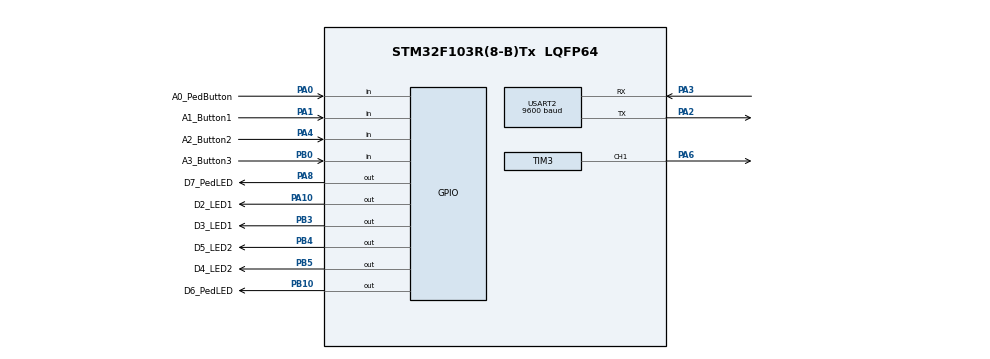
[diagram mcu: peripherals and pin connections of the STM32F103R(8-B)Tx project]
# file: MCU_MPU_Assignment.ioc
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Mcu.Family=STM32F1
Mcu.Name=STM32F103R(8-B)Tx
Mcu.Package=LQFP64
NVIC.PriorityGroup=NVIC_PRIORITYGROUP_4
NVIC.TIM2_IRQn=true\:0\:0\:false\:false\:true\:true\:true
NVIC.TIM3_IRQn=true\:0\:0\:false\:false\:true\:true\:true
NVIC.USART2_IRQn=true\:0\:0\:false\:false\:true\:true\:true
PA0-WKUP.GPIO_Label=A0_PedButton
PA0-WKUP.GPIO_PuPd=GPIO_PULLUP
PA0-WKUP.Signal=GPIO_Input
PA1.GPIO_Label=A1_Button1
PA1.GPIO_PuPd=GPIO_PULLUP
PA1.Signal=GPIO_Input
PA10.GPIO_Label=D2_LED1
PA10.Signal=GPIO_Output
PA13.Mode=Serial_Wire
PA13.Signal=SYS_JTMS-SWDIO
PA14.Mode=Serial_Wire
PA14.Signal=SYS_JTCK-SWCLK
PA2.Mode=Asynchronous
PA2.Signal=USART2_TX
PA3.Mode=Asynchronous
PA3.Signal=USART2_RX
PA4.GPIO_Label=A2_Button2
PA4.GPIO_PuPd=GPIO_PULLUP
PA4.Signal=GPIO_Input
PA6.Signal=S_TIM3_CH1
PA8.GPIO_Label=D7_PedLED
PA8.Signal=GPIO_Output
PB0.GPIO_Label=A3_Button3
PB0.GPIO_PuPd=GPIO_PULLUP
PB0.Signal=GPIO_Input
PB10.GPIO_Label=D6_PedLED
PB10.Signal=GPIO_Output
PB3.GPIO_Label=D3_LED1
PB3.Signal=GPIO_Output
PB4.GPIO_Label=D5_LED2
PB4.Signal=GPIO_Output
PB5.GPIO_Label=D4_LED2
PB5.Signal=GPIO_Output
ProjectManager.HeapSize=0x200
ProjectManager.StackSize=0x400
ProjectManager.TargetToolchain=STM32CubeIDE
RCC.APB1Freq_Value=8000000
RCC.APB2Freq_Value=8000000
SH.S_TIM3_CH1.0=TIM3_CH1,PWM Generation1 CH1
TIM2.Period=9
TIM2.Prescaler=7999
TIM3.Channel-PWM\ Generation1\ CH1=TIM_CHANNEL_1
TIM3.Period=9
TIM3.Prescaler=7999
USART2.BaudRate=9600
USART2.VirtualMode=VM_ASYNC
VP_TIM2_VS_ClockSourceINT.Mode=Internal
VP_TIM3_VS_ClockSourceINT.Mode=Internal
board=custom

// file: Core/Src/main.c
/* USER CODE BEGIN Header */
/**
  ******************************************************************************
  * @file           : main.c
  * @brief          : Main program body
  ******************************************************************************
  * @attention
  *
  * <h2><center>&copy; Copyright (c) 2023 STMicroelectronics.
  * All rights reserved.</center></h2>
  *
  * This software component is licensed by ST under BSD 3-Clause license,
  * the "License"; You may not use this file except in compliance with the
  * License. You may obtain a copy of the License at:
  *                        opensource.org/licenses/BSD-3-Clause
  *
  ******************************************************************************
  */
/* USER CODE END Header */
#include "main.h"

/* USER CODE BEGIN Includes */
#include "global.h"
#include "timer.h"
#include "fsm_automatic.h"
#include "fsm_manual.h"
#include "input_processing.h"
#include "input_reading.h"
#include "uart.h"
#include "scheduler.h"
/* USER CODE END Includes */

TIM_HandleTypeDef htim2;
TIM_HandleTypeDef htim3;

UART_HandleTypeDef huart2;

void SystemClock_Config(void);
static void MX_GPIO_Init(void);
static void MX_TIM2_Init(void);
static void MX_TIM3_Init(void);
static void MX_USART2_UART_Init(void);

/* USER CODE BEGIN 0 */
void buzzer(int vol){
	__HAL_TIM_SET_COMPARE(&htim3, TIM_CHANNEL_1, vol);
}
/* USER CODE END 0 */

int main(void)
{

  /* MCU Configuration--------------------------------------------------------*/

  /* Reset of all peripherals, Initializes the Flash interface and the Systick. */
  HAL_Init();

  /* Configure the system clock */
  SystemClock_Config();

  /* Initialize all configured peripherals */
  MX_GPIO_Init();
  MX_TIM2_Init();
  MX_TIM3_Init();
  MX_USART2_UART_Init();
  /* USER CODE BEGIN 2 */
  HAL_TIM_Base_Start_IT(&htim2);
  HAL_TIM_Base_Start_IT(&htim3);
  HAL_TIM_PWM_Start(&htim3, TIM_CHANNEL_1);

  setTimer6(500);
  SCH_Add_Task(timer_run, 0, 1);
  SCH_Add_Task(button_reading, 0, 1);
  SCH_Add_Task(fsm_automatic, 0, 1);
  SCH_Add_Task(fsm_red_manual, 0, 1);
  SCH_Add_Task(fsm_amber_manual, 0, 1);
  SCH_Add_Task(fsm_green_manual, 0, 1);
  SCH_Add_Task(fsm_button_processing, 0, 1);
  /* USER CODE END 2 */

  /* Infinite loop */
  /* USER CODE BEGIN WHILE */
  while (1)
  {
	  SCH_Dispatch_Tasks();
    /* USER CODE END WHILE */

  }
}

void SystemClock_Config(void)
{
  RCC_OscInitTypeDef RCC_OscInitStruct = {0};
  RCC_ClkInitTypeDef RCC_ClkInitStruct = {0};

  /** Initializes the RCC Oscillators according to the specified parameters
  * in the RCC_OscInitTypeDef structure.
  */
  RCC_OscInitStruct.OscillatorType = RCC_OSCILLATORTYPE_HSI;
  RCC_OscInitStruct.HSIState = RCC_HSI_ON;
  RCC_OscInitStruct.HSICalibrationValue = RCC_HSICALIBRATION_DEFAULT;
  RCC_OscInitStruct.PLL.PLLState = RCC_PLL_ON;
  RCC_OscInitStruct.PLL.PLLSource = RCC_PLLSOURCE_HSI_DIV2;
  RCC_OscInitStruct.PLL.PLLMUL = RCC_PLL_MUL2;
  if (HAL_RCC_OscConfig(&RCC_OscInitStruct) != HAL_OK)
  {
    Error_Handler();
  }

  /** Initializes the CPU, AHB and APB buses clocks
  */
  RCC_ClkInitStruct.ClockType = RCC_CLOCKTYPE_HCLK|RCC_CLOCKTYPE_SYSCLK
                              |RCC_CLOCKTYPE_PCLK1|RCC_CLOCKTYPE_PCLK2;
  RCC_ClkInitStruct.SYSCLKSource = RCC_SYSCLKSOURCE_PLLCLK;
  RCC_ClkInitStruct.AHBCLKDivider = RCC_SYSCLK_DIV1;
  RCC_ClkInitStruct.APB1CLKDivider = RCC_HCLK_DIV2;
  RCC_ClkInitStruct.APB2CLKDivider = RCC_HCLK_DIV1;

  if (HAL_RCC_ClockConfig(&RCC_ClkInitStruct, FLASH_LATENCY_0) != HAL_OK)
  {
    Error_Handler();
  }
}

static void MX_TIM2_Init(void)
{

  TIM_ClockConfigTypeDef sClockSourceConfig = {0};
  TIM_MasterConfigTypeDef sMasterConfig = {0};

  htim2.Instance = TIM2;
  htim2.Init.Prescaler = 7999;
  htim2.Init.CounterMode = TIM_COUNTERMODE_UP;
  htim2.Init.Period = 9;
  htim2.Init.ClockDivision = TIM_CLOCKDIVISION_DIV1;
  htim2.Init.AutoReloadPreload = TIM_AUTORELOAD_PRELOAD_DISABLE;
  if (HAL_TIM_Base_Init(&htim2) != HAL_OK)
  {
    Error_Handler();
  }
  sClockSourceConfig.ClockSource = TIM_CLOCKSOURCE_INTERNAL;
  if (HAL_TIM_ConfigClockSource(&htim2, &sClockSourceConfig) != HAL_OK)
  {
    Error_Handler();
  }
  sMasterConfig.MasterOutputTrigger = TIM_TRGO_RESET;
  sMasterConfig.MasterSlaveMode = TIM_MASTERSLAVEMODE_DISABLE;
  if (HAL_TIMEx_MasterConfigSynchronization(&htim2, &sMasterConfig) != HAL_OK)
  {
    Error_Handler();
  }

}

static void MX_TIM3_Init(void)
{

  TIM_ClockConfigTypeDef sClockSourceConfig = {0};
  TIM_MasterConfigTypeDef sMasterConfig = {0};
  TIM_OC_InitTypeDef sConfigOC = {0};

  htim3.Instance = TIM3;
  htim3.Init.Prescaler = 7999;
  htim3.Init.CounterMode = TIM_COUNTERMODE_UP;
  htim3.Init.Period = 9;
  htim3.Init.ClockDivision = TIM_CLOCKDIVISION_DIV1;
  htim3.Init.AutoReloadPreload = TIM_AUTORELOAD_PRELOAD_DISABLE;
  if (HAL_TIM_Base_Init(&htim3) != HAL_OK)
  {
    Error_Handler();
  }
  sClockSourceConfig.ClockSource = TIM_CLOCKSOURCE_INTERNAL;
  if (HAL_TIM_ConfigClockSource(&htim3, &sClockSourceConfig) != HAL_OK)
  {
    Error_Handler();
  }
  if (HAL_TIM_PWM_Init(&htim3) != HAL_OK)
  {
    Error_Handler();
  }
  sMasterConfig.MasterOutputTrigger = TIM_TRGO_RESET;
  sMasterConfig.MasterSlaveMode = TIM_MASTERSLAVEMODE_DISABLE;
  if (HAL_TIMEx_MasterConfigSynchronization(&htim3, &sMasterConfig) != HAL_OK)
  {
    Error_Handler();
  }
  sConfigOC.OCMode = TIM_OCMODE_PWM1;
  sConfigOC.Pulse = 0;
  sConfigOC.OCPolarity = TIM_OCPOLARITY_HIGH;
  sConfigOC.OCFastMode = TIM_OCFAST_DISABLE;
  if (HAL_TIM_PWM_ConfigChannel(&htim3, &sConfigOC, TIM_CHANNEL_1) != HAL_OK)
  {
    Error_Handler();
  }
  HAL_TIM_MspPostInit(&htim3);

}

static void MX_USART2_UART_Init(void)
{

  huart2.Instance = USART2;
  huart2.Init.BaudRate = 9600;
  huart2.Init.WordLength = UART_WORDLENGTH_8B;
  huart2.Init.StopBits = UART_STOPBITS_1;
  huart2.Init.Parity = UART_PARITY_NONE;
  huart2.Init.Mode = UART_MODE_TX_RX;
  huart2.Init.HwFlowCtl = UART_HWCONTROL_NONE;
  huart2.Init.OverSampling = UART_OVERSAMPLING_16;
  if (HAL_UART_Init(&huart2) != HAL_OK)
  {
    Error_Handler();
  }

}

static void MX_GPIO_Init(void)
{
  GPIO_InitTypeDef GPIO_InitStruct = {0};

  /* GPIO Ports Clock Enable */
  __HAL_RCC_GPIOA_CLK_ENABLE();
  __HAL_RCC_GPIOB_CLK_ENABLE();

  /*Configure GPIO pin Output Level */
  HAL_GPIO_WritePin(GPIOB, D6_PedLED_Pin|D3_LED1_Pin|D5_LED2_Pin|D4_LED2_Pin, GPIO_PIN_RESET);

  /*Configure GPIO pin Output Level */
  HAL_GPIO_WritePin(GPIOA, D7_PedLED_Pin|D2_LED1_Pin, GPIO_PIN_RESET);

  /*Configure GPIO pins : A0_PedButton_Pin A1_Button1_Pin A2_Button2_Pin */
  GPIO_InitStruct.Pin = A0_PedButton_Pin|A1_Button1_Pin|A2_Button2_Pin;
  GPIO_InitStruct.Mode = GPIO_MODE_INPUT;
  GPIO_InitStruct.Pull = GPIO_NOPULL;
  HAL_GPIO_Init(GPIOA, &GPIO_InitStruct);

  /*Configure GPIO pin : A3_Button3_Pin */
  GPIO_InitStruct.Pin = A3_Button3_Pin;
  GPIO_InitStruct.Mode = GPIO_MODE_INPUT;
  GPIO_InitStruct.Pull = GPIO_NOPULL;
  HAL_GPIO_Init(A3_Button3_GPIO_Port, &GPIO_InitStruct);

  /*Configure GPIO pins : D6_PedLED_Pin D3_LED1_Pin D5_LED2_Pin D4_LED2_Pin */
  GPIO_InitStruct.Pin = D6_PedLED_Pin|D3_LED1_Pin|D5_LED2_Pin|D4_LED2_Pin;
  GPIO_InitStruct.Mode = GPIO_MODE_OUTPUT_PP;
  GPIO_InitStruct.Pull = GPIO_NOPULL;
  GPIO_InitStruct.Speed = GPIO_SPEED_FREQ_LOW;
  HAL_GPIO_Init(GPIOB, &GPIO_InitStruct);

  /*Configure GPIO pins : D7_PedLED_Pin D2_LED1_Pin */
  GPIO_InitStruct.Pin = D7_PedLED_Pin|D2_LED1_Pin;
  GPIO_InitStruct.Mode = GPIO_MODE_OUTPUT_PP;
  GPIO_InitStruct.Pull = GPIO_NOPULL;
  GPIO_InitStruct.Speed = GPIO_SPEED_FREQ_LOW;
  HAL_GPIO_Init(GPIOA, &GPIO_InitStruct);

}

/* USER CODE BEGIN 4 */
void HAL_TIM_PeriodElapsedCallback(TIM_HandleTypeDef *htim2) {
	SCH_Update();
}
/* USER CODE END 4 */

void Error_Handler(void)
{
  __disable_irq();
  while (1)
  {
  }
}
